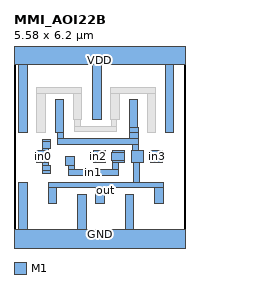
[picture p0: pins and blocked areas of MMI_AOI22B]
MACRO MMI_AOI22B
	CLASS CORE ;
	FOREIGN MMI_AOI22B 0 0 ;
	SIZE 5.58 BY 6.2 ;
	SYMMETRY X Y ;
	SITE CORE1 ;
	PIN out
		DIRECTION output ;
		USE SIGNAL ;
		PORT
			LAYER M1 ;
			RECT 1.34 3.585 1.62 4.645 ;
			LAYER M1 ;
			RECT 3.755 3.73 4.035 4.645 ;
			LAYER M1 ;
			RECT 3.755 3.585 4.055 3.73 ;
			LAYER M1 ;
			RECT 1.425 3.375 1.615 3.585 ;
			LAYER M1 ;
			RECT 3.77 3.375 4.055 3.585 ;
			LAYER M1 ;
			RECT 1.425 3.18 4.055 3.375 ;
			LAYER M1 ;
			RECT 3.865 2.98 4.055 3.18 ;
			LAYER M1 ;
			RECT 3.84 2.6 4.22 2.98 ;
			LAYER M1 ;
			RECT 3.9 1.955 4.095 2.6 ;
			LAYER M1 ;
			RECT 1.115 1.765 4.875 1.955 ;
			LAYER M1 ;
			RECT 1.12 1.255 1.4 1.765 ;
			LAYER M1 ;
			RECT 2.67 1.255 2.95 1.765 ;
			LAYER M1 ;
			RECT 4.59 1.255 4.87 1.765 ;
		END
		AntennaDiffArea 2.3023 ;
	END out
	PIN in1
		DIRECTION input ;
		USE SIGNAL ;
		PORT
			LAYER M1 ;
			RECT 3.22 2.93 3.6 2.98 ;
			LAYER M1 ;
			RECT 1.685 2.51 1.965 2.79 ;
			LAYER M1 ;
			RECT 3.18 2.65 3.6 2.93 ;
			LAYER M1 ;
			RECT 1.775 2.36 1.965 2.51 ;
			LAYER M1 ;
			RECT 3.215 2.6 3.6 2.65 ;
			LAYER M1 ;
			RECT 3.215 2.36 3.405 2.6 ;
			LAYER M1 ;
			RECT 1.775 2.165 3.405 2.36 ;
		END
		AntennaGateArea 0.693 ;
	END in1
	PIN GND
		DIRECTION inout ;
		USE GROUND ;
		PORT
			LAYER M1 ;
			RECT 0.16 0.42 0.44 1.955 ;
			LAYER M1 ;
			RECT 2.08 0.42 2.36 1.535 ;
			LAYER M1 ;
			RECT 3.63 0.42 3.91 1.535 ;
			LAYER M1 ;
			RECT 0 -0.42 5.58 0.42 ;
		END
	END GND
	PIN in2
		DIRECTION input ;
		USE SIGNAL ;
		PORT
			LAYER M1 ;
			RECT 2.6 2.93 2.98 2.98 ;
			LAYER M1 ;
			RECT 2.53 2.65 2.98 2.93 ;
			LAYER M1 ;
			RECT 2.6 2.6 2.98 2.65 ;
		END
		AntennaGateArea 0.693 ;
	END in2
	PIN VDD
		DIRECTION inout ;
		USE POWER ;
		PORT
			LAYER M1 ;
			RECT 0 5.78 5.58 6.62 ;
			LAYER M1 ;
			RECT 0.16 3.585 0.44 5.78 ;
			LAYER M1 ;
			RECT 2.575 3.985 2.855 5.78 ;
			LAYER M1 ;
			RECT 4.935 3.585 5.215 5.78 ;
		END
	END VDD
	PIN in3
		DIRECTION input ;
		USE SIGNAL ;
		PORT
			LAYER M1 ;
			RECT 4.46 2.6 4.84 2.98 ;
		END
		AntennaGateArea 0.693 ;
	END in3
	PIN in0
		DIRECTION input ;
		USE SIGNAL ;
		PORT
			LAYER M1 ;
			RECT 0.925 3.265 1.205 3.34 ;
			LAYER M1 ;
			RECT 0.915 3.06 1.205 3.265 ;
			LAYER M1 ;
			RECT 0.915 2.98 1.12 3.06 ;
			LAYER M1 ;
			RECT 0.74 2.6 1.12 2.98 ;
			LAYER M1 ;
			RECT 0.92 2.51 1.12 2.6 ;
			LAYER M1 ;
			RECT 0.92 2.32 1.205 2.51 ;
			LAYER M1 ;
			RECT 0.925 2.23 1.205 2.32 ;
		END
		AntennaGateArea 0.693 ;
	END in0
	OBS
		LAYER M1 ;
		RECT 0.75 5.045 1.03 5.055 ;
		LAYER M1 ;
		RECT 1.93 5.045 2.21 5.055 ;
		LAYER M1 ;
		RECT 0.75 4.85 2.21 5.045 ;
		LAYER M1 ;
		RECT 0.75 3.585 1.03 4.85 ;
		LAYER M1 ;
		RECT 1.93 3.995 2.21 4.85 ;
		LAYER M1 ;
		RECT 1.98 3.785 2.175 3.995 ;
		LAYER M1 ;
		RECT 3.165 5.05 3.445 5.055 ;
		LAYER M1 ;
		RECT 4.345 5.05 4.625 5.055 ;
		LAYER M1 ;
		RECT 3.165 4.855 4.625 5.05 ;
		LAYER M1 ;
		RECT 3.165 3.985 3.445 4.855 ;
		LAYER M1 ;
		RECT 3.17 3.785 3.36 3.985 ;
		LAYER M1 ;
		RECT 1.98 3.59 3.36 3.785 ;
		LAYER M1 ;
		RECT 4.345 3.585 4.625 4.855 ;
	END
END MMI_AOI22B
